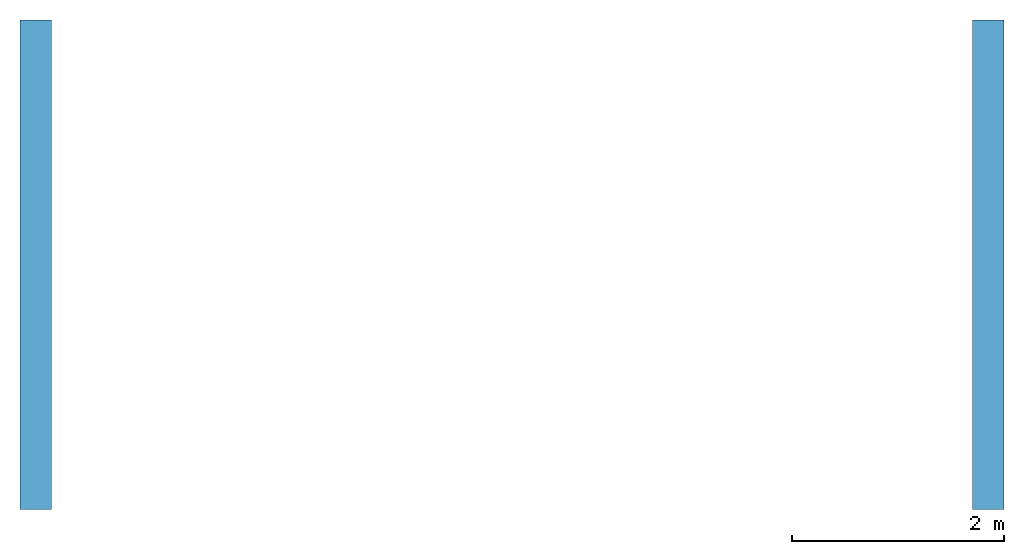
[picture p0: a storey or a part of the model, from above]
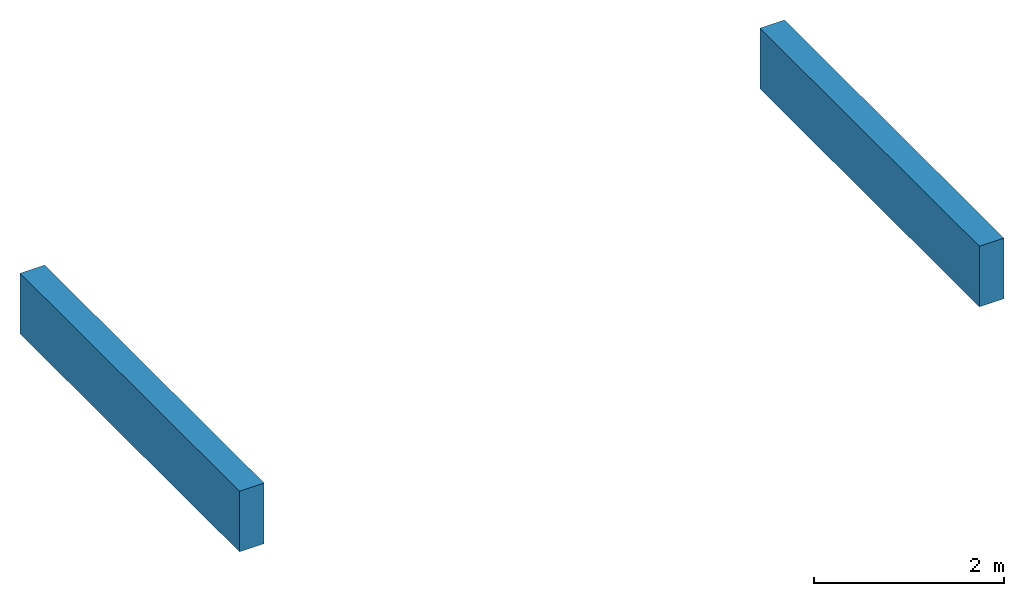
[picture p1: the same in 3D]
Properties of the parts of a building model (IFC2X3)

# File
Description: ViewDefinition [CoordinationView]
File name: GM.TO-350-101.1 (EDITED).ifc (Edited by Naviate Simple BIM 2022 version 6)
Time: 2026-03-17T17:04:53+01:00
Written by: ODA SDAI 24.12
Made in: Autodesk Revit 25.4.20.11 (ENU) - IFC 25.4.0.27

# IfcProject, A181143
LongName: T2; Phase: Detaljprosjekt

# IfcSite (9)
Name | RefLatitude | RefLongitude | RefElevation (mm) | Reference latitude | Reference elevation | Reference longitude
ENGM | 33, 12, 51, 119999 | -97, -7, -51, -239999 | -4.85124e-10
 | 33, 12, 51, 119999 | -97, -7, -51, -239999 | 0
 | 33, 12, 51, 119999 | -97, -7, -51, -239999 | 0 | 33, 12, 51, 119999 | 0 | -97, -7, -51, -239999
4 x ENGM | 59, 54, 49, 759826 | 10, 44, 19, 467315 | 0 | 59, 54, 49, 759826 | 0 | 10, 44, 19, 467315 | MagiCAD Pset_Site - Name: ENGM
Gardermoen
Default | 59, 54, 49, 759826 | 10, 44, 19, 467315 | 0

# IfcBuilding (9)
Name
TS | LongName: TS; Pset_BuildingCommon - NumberOfStoreys: 16
2 x mc-building
4 x TS | MagiCAD Pset_Building - Building name: TS
TS
 | Pset_BuildingCommon - NumberOfStoreys: 13

# IfcBuildingStorey (13)
Name | In | Elevation (mm) | Name
Nivå E | mc-building | 207370
Nivå D | mc-building | 204000
Nivå E | mc-building | 207370 | Nivå E
Nivå C | mc-building | 200300 | Nivå C
Nivå D | mc-building | 204000 | Nivå D
Nivå D + 1,2 m | mc-building | 205200 | Nivå D + 1,2 m
3 x Nivå D | TS | 204000 | Nivå D
D | TS | 0
B | TS | 0
2 x Nivå C | TS | 200300 | Nivå C

# IfcBuildingStorey: Level:8mm Head (2)
Pset_AirSideSystemInformation - sets with these values: 2
Name | LongName = Name | Elevation (mm)
Nivå C | Nivå C | 200300
Nivå D | Nivå D | 204000

# IfcBuildingStorey: Level:T2 - Kote (4)
In: TS
Name | LongName | Elevation (mm) | Pset_AirSideSystemInformation, Name | Pset_AirSideSystemInformation, sets with these values
Nivå C + 2,03 m | Nivå C + 2,03 m | 202330 | Nivå C + 2,03 m | 2
Nivå D | Nivå D | 204000 | Nivå D | 2
Nivå D + 1,2 m | Nivå D + 1,2 m | 205200 | Nivå D + 1,2 m | 2
Nivå E | Nivå E | 207370 | Pset_ProductRequirements - Name: Nivå E; sets with these values: 2

# IfcBeam: B223 - Bjelke - HUP:B223 - HUP 80x80x4 (5)
Type - Pset_BeamCommon - LoadBearing: yes
Material: _NSW Stål
Pset_BeamCommon - IsExternal: no; Slope: 0 deg; Reference: B223 - HUP 80x80x4; Span: 5920 mm
ePset_SimplebimBasicQuantities - Volume, net (Simplebim): 0.00719872 m3; Height (Simplebim): 80 mm; Width (Simplebim): 80 mm; Area, sides, net (Simplebim): 3.60179 m2; Length (Simplebim): 5920 mm; Weight, as steel (Simplebim): 56.51 kg
ePset_LocationTool - Splitting: ORIGINAL
Pset_QuantityTakeOff - Reference: B223 - HUP 80x80x4; sets with these values: 2
ePset_Simplebim - Assembly Level: Leaf
AVINOR - 07_Fase: F90; 08_Status: S1; 03_Ansvar: FDV; 06_Omrade: TS; 01_Lufthavnkode: ENGM
Name (B223 - Bjelke - HUP:B223 - HUP 80x80x4:...) | In
24003916 | Nivå E
24003994 | Nivå D
24003995 | Nivå E
24004007 | Nivå D
24004008 | Nivå E

# IfcBeam: RHS160*80*5 (4)
In: D
Description: RHS160*80*5; Material: STEEL/S355
ePset_LocationTool - Splitting: ORIGINAL
ePset_SimplebimBasicQuantities - Width (Simplebim): 80 mm; Height (Simplebim): 160 mm
Tekla Quantity - Width: 80 mm; Heigth: 160 mm
AVINOR - 07_Fase: F90; 02_Prosjekt: T1; 04_Kontrakt: FDV; 03_Ansvar: FDV; 08_Status: S2; 06_Omrade: TS; 01_Lufthavnkode: ENGM
ePset_Simplebim - Assembly Level: Leaf
Tekla Common - Grade: S355; Name: STÅLBJELKE; Bottom elevation: +207.090; Top elevation: +207.250; Profile: RHS160*80*5; Class: 330
Pset_BeamCommon - LoadBearing: no
Name | Area, sides, net (Simplebim) (m2) | Length (Simplebim) (mm) = Length (mm) | Weight, as steel (Simplebim) (kg) = WEIGTH_NET (kg) | Volume, net (Simplebim) (m3) | VOLUME_NET (m3) | WEIGTH_GROSS (kg) | VOLUME_GROSS (m3) | AREA_NET (m2) | AREA_GROSS (m2) | Assembly mark | Part mark = Reference
2 x STÅLBJELKE | 6.90371 | 7499.03 | 135.395 | 0.0172478 | 0.01724 | 134.806 | 0.01716 | 3.5632 | 3.51705 | SB-3277(?) | DSB-7490(?)
2 x STÅLBJELKE | 6.76568 | 7349 | 132.686 | 0.0169027 | 0.01689 | 132.109 | 0.01683 | 3.49196 | 3.44668 | SB-3275(?) | DSB-7488(?)

# IfcBeam: RHS80*5 (22)
In: D
Description: RHS80*5
Pset_BeamCommon - LoadBearing: no
AVINOR - 07_Fase: F90; 02_Prosjekt: T1; 04_Kontrakt: FDV; 03_Ansvar: FDV; 08_Status: S2; 06_Omrade: TS; 01_Lufthavnkode: ENGM
Tekla Common - Grade: S355; Profile: RHS80*5; Name: STÅLBJELKE; Class: 330
ePset_Simplebim - Assembly Level: Leaf
ePset_SimplebimBasicQuantities - Width (Simplebim): 80 mm
Name | Material | WEIGTH_NET (kg) | AREA_NET (m2) | Length (mm) | VOLUME_GROSS (m3) | AREA_GROSS (m2) | Heigth (mm) = Width (mm) | WEIGTH_GROSS (kg) | VOLUME_NET (m3) | Reference = Part mark | Splitting | Assembly mark | Top elevation | Bottom elevation | Volume, net (Simplebim) (m3) | Height (Simplebim) (mm) | Weight, as steel (Simplebim) (kg) | Length (Simplebim) (mm) | Area, sides, net (Simplebim) (m2)
15 x STÅLBJELKE | STEEL/S355 | 6.94726 | 0.1904 | 590.001 | 0.00087 | 0.18231 | 80 | 6.90094 | 0.00089 | DSB-15340(?) | ORIGINAL | SB-3284(?) | +207.170 | +206.580 | 0.000885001 | 590.001 | 6.94726 | 80 | 0.357
STÅLBJELKE | STEEL/S355 | 16.7088 | 0.45568 | 1419.01 | 0.00211 | 0.43847 | 80 | 16.5974 | 0.00214 | DSB-7509(?) | ORIGINAL | SB-3289(?) | +206.210 | +206.130 | 0.00212851 | 80 | 16.7088 | 1419.01 | 0.854403
STÅLBJELKE | STEEL/S355 | 4.79243 | 0.13184 | 407 | 0.00062 | 0.12576 | 80 | 4.76048 | 0.00062 | DSB-7506(?) | ORIGINAL | SB-3286(?) | +206.580 | +206.500 | 0.0006105 | 80 | 4.79242 | 407 | 0.2472
STÅLBJELKE | STEEL/S355 | 63.9737 | 1.74016 | 5433.01 | 0.0081 | 1.6788 | 80 | 63.5472 | 0.00815 | DSB-7507(?) | ORIGINAL | SB-3287(?) | +206.580 | +206.500 | 0.00814951 | 80 | 63.9737 | 5433.01 | 3.26281
STÅLBJELKE | STEEL/S355 | 69.708 | 1.896 | 5920 | 0.00882 | 1.82928 | 80 | 69.2433 | 0.00887 | DSB-7508(?) | ORIGINAL | SB-3288(?) | +206.580 | +206.500 | 0.00888 | 80 | 69.708 | 5920 | 3.555
STÅLBJELKE | STEEL/S355 | 63.9736 | 1.74016 | 5433 | 0.0081 | 1.6788 | 80 | 63.5471 | 0.00815 | DSB-7507(?) | ORIGINAL | SB-3287(?) | +206.580 | +206.500 | 0.00814951 | 80 | 63.9737 | 5433.01 | 3.26281
STÅLBJELKE | STEEL/S355 | 4.79233 | 0.13184 | 406.992 | 0.00062 | 0.12576 | 80 | 4.76038 | 0.00062 | DSB-7506(?) | ORIGINAL | SB-3286(?) | +206.580 | +206.500 | 0.0006105 | 80 | 4.79242 | 407 | 0.2472
STÅLBJELKE |  |  |  |  |  |  |  |  |  | DSB-7504(?) | RESULT | SB-3284(?) | +207.250 | +207.170 | 0.0260302 | 80 | 204.337 | 17353 | 10.4151

# IfcBuildingElementProxy, KRO Damphette 1350x1400x500_tilkobling i front
In: Nivå D
ePset_LocationTool - Splitting: ORIGINAL
ePset_Simplebim - Assembly Level: Leaf
ePset_SimplebimBasicQuantities - Area, largest surface, net (Simplebim): 1.89 m2; Length (Simplebim): 1420 mm; Volume, net (Simplebim): 0.9466 m3; Height (Simplebim): 500 mm; Thickness (Simplebim): 1350 mm
Group: +TS=360.034 A (1)

# IfcBuildingElementProxy: A234 - Gitter:A241 - Gitter 200 x 200_UK_2600, A234 - Gitter:A241 - Gitter 200 x 200_UK_2600:30921747
In: Nivå D
Type - Material: <Unnamed>
Pset_BuildingElementProxyCommon - Reference: A241 - Gitter 200 x 200_UK_2600; sets with these values: 2
AVINOR - 07_Fase: F90; 08_Status: S1; 03_Ansvar: FDV; 06_Omrade: TS; 01_Lufthavnkode: ENGM
ePset_Simplebim - Assembly Level: Leaf
ePset_SimplebimBasicQuantities - Volume, net (Simplebim): 0.90288 m3; Area, largest surface, net (Simplebim): 4.104 m2; Length (Simplebim): 17100 mm; Thickness (Simplebim): 240 mm; Height (Simplebim): 220 mm
ePset_LocationTool - Splitting: ORIGINAL

# IfcColumn: PL15*260 (12)
In: D
Description: PL15*260; Material: STEEL/S355
Pset_ColumnCommon - LoadBearing: no; Reference: DSS-5570(?)
Tekla Quantity - VOLUME_NET: 0.00047 m3; VOLUME_GROSS: 0.00047 m3; AREA_NET: 0.0738 m2; AREA_GROSS: 0.0738 m2; WEIGTH_GROSS: 3.6738 kg; WEIGTH_NET: 3.6738 kg; Width: 15 mm; Length: 120 mm; Heigth: 260 mm
ePset_SimplebimBasicQuantities - Volume, net (Simplebim): 0.000468 m3; Weight, as steel (Simplebim): 3.6738 kg; Area, sides, net (Simplebim): 0.0114 m2; Width (Simplebim): 15 mm; Depth (Simplebim): 120 mm; Height (Simplebim): 260 mm
AVINOR - 07_Fase: F90; 02_Prosjekt: T1; 03_Ansvar: FDV; 04_Kontrakt: FDV; 08_Status: S2; 06_Omrade: TS; 01_Lufthavnkode: ENGM
ePset_LocationTool - Splitting: ORIGINAL
Tekla Common - Grade: S355; Class: 320; Profile: PL15*260; Name: STÅLSØYLE; Part mark: DSS-5570(?)
ePset_Simplebim - Assembly Level: Leaf
Name | Assembly mark | Bottom elevation | Top elevation
6 x STÅLSØYLE | SS-2790(?) | +203.930 | +203.945
STÅLSØYLE | SS-8193(?) | +203.935 | +203.950
4 x STÅLSØYLE | SS-2789(?) | +203.930 | +203.945
STÅLSØYLE | SS-1401(?) | +203.930 | +203.945

# IfcColumn: RHS80*5 (12)
In: D
Description: RHS80*5; Material: STEEL/S355
ePset_LocationTool - Splitting: ORIGINAL
Tekla Common - Grade: S355; Profile: RHS80*5; Class: 320; Name: STÅLSØYLE
ePset_SimplebimBasicQuantities - Width (Simplebim): 80 mm; Depth (Simplebim): 80 mm
AVINOR - 07_Fase: F90; 02_Prosjekt: T1; 03_Ansvar: FDV; 04_Kontrakt: FDV; 08_Status: S2; 06_Omrade: TS; 01_Lufthavnkode: ENGM
Pset_ColumnCommon - LoadBearing: no
ePset_Simplebim - Assembly Level: Leaf
Tekla Quantity - Width: 80 mm; Heigth: 80 mm
Name | Assembly mark | Part mark = Reference | Top elevation | Bottom elevation | Volume, net (Simplebim) (m3) | Height (Simplebim) (mm) = Length (mm) | Area, sides, net (Simplebim) (m2) | Weight, as steel (Simplebim) (kg) = WEIGTH_NET (kg) | AREA_NET (m2) | VOLUME_NET (m3) | WEIGTH_GROSS (kg) | AREA_GROSS (m2) | VOLUME_GROSS (m3)
6 x STÅLSØYLE | SS-2790(?) | DSS-1715(?) | +207.090 | +203.945 | 0.0047175 | 3145 | 1.887 | 37.0324 | 1.008 | 0.00471 | 36.7855 | 0.9718 | 0.00469
STÅLSØYLE | SS-8193(?) | DSS-3492(?) | +207.170 | +203.950 | 0.00483 | 3220 | 1.932 | 37.9155 | 1.032 | 0.00483 | 37.6627 | 0.99498 | 0.0048
4 x STÅLSØYLE | SS-2789(?) | DSS-1716(?) | +207.170 | +203.945 | 0.0048375 | 3225 | 1.935 | 37.9744 | 1.0336 | 0.00484 | 37.7212 | 0.99652 | 0.0048
STÅLSØYLE | SS-1401(?) | DSS-1716(?) | +207.170 | +203.945 | 0.0048375 | 3225 | 1.935 | 37.9744 | 1.0336 | 0.00484 | 37.7212 | 0.99652 | 0.0048

# IfcCovering (33)
PredefinedType: INSULATION
ePset_LocationTool - Splitting: ORIGINAL
ePset_Simplebim - Assembly Level: Leaf
Name | In | Description | Volume, net (Simplebim) (m3) | Length (Simplebim) (mm) | Height (Simplebim) (mm) | Width (Simplebim) (mm) | Area, largest surface, net (Simplebim) (m2)
EI30-30 | Nivå E | EI30 Brannisolasjon 30 mm | 0.102218 | 3159.7 | 375 | 375 | 3.71771
EI30-30 | Nivå E | EI30 Brannisolasjon 30 mm | 0.0403898 | 1248.5 | 375 | 375 | 1.46899
EI30-30 | Nivå E | EI30 Brannisolasjon 30 mm | 0.0269438 | 412.344 | 375 | 355.321 | 0.289607
EI30-30 | Nivå E | EI30 Brannisolasjon 30 mm | 0.0322994 | 376.5 | 376.5 | 375 | 0.346444
T=25mm | Nivå E | 25mm lamellmatte | 0.000823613 | 365 | 31 | 365 | 0.035502
EI30-30 | Nivå E | EI30 Brannisolasjon 30 mm | 0.00602371 | 55 | 375 | 375 | 0.109522
EI30-30 | Nivå E | EI30 Brannisolasjon 30 mm | 0.0811775 | 2509.3 | 375 | 375 | 2.95245
EI30-30 | Nivå E | EI30 Brannisolasjon 30 mm | 0.0537249 | 502.5 | 375 | 502.5 | 0.57858
EI30-30 | Nivå D | EI30 Brannisolasjon 30 mm | 0.0242953 | 751 | 375 | 375 | 0.883628
T=25mm | Nivå D | 25mm lamellmatte | 0.0619889 | 2333.2 | 365 | 365 | 2.67204
EI30-50 | Nivå D | EI30 Brannisolasjon 50 mm | 0.0110508 | 350 | 235.7 | 350 | 0.258837
T=25mm | Nivå D | 25mm lamellmatte | 0.00566433 | 213.2 | 365 | 365 | 0.244162
T=25mm | Nivå D | 25mm lamellmatte | 0.00458301 | 365 | 172.5 | 365 | 0.197552
T=25mm | Nivå D | 25mm lamellmatte | 0.030022 | 1130 | 365 | 365 | 1.29411
T=25mm | Nivå D | 25mm lamellmatte | 0.0305888 | 365 | 371.5 | 371.5 | 0.338062
T=25mm | Nivå D | 25mm lamellmatte | 0.0225404 | 848.4 | 365 | 365 | 0.97161
T=25mm | Nivå D | 25mm lamellmatte | 0.0182478 | 365 | 176.404 | 365 | 0.201702
2 x EI30-50 | Nivå D | EI30 Brannisolasjon 50 mm | 0.0188986 | 483.7 | 300 | 300 | 0.455298
EI30-50 | Nivå D | EI30 Brannisolasjon 50 mm | 0.0444048 | 947.1 | 350 | 350 | 1.04007
EI30-50 | Nivå D | EI30 Brannisolasjon 50 mm | 0.00615391 | 88.0625 | 300 | 300 | 0.0827602
EI30-50 | Nivå D | EI30 Brannisolasjon 50 mm | 0.0061529 | 88.048 | 300 | 300 | 0.0827465
EI30-50 | Nivå D | EI30 Brannisolasjon 50 mm | 0.00570696 | 60 | 350 | 350 | 0.095116
EI30-30 | Nivå D | EI30 Brannisolasjon 30 mm | 0.00276153 | 58.9 | 350 | 350 | 0.0646818
EI30-30 | Nivå D | EI30 Brannisolasjon 30 mm | 0.0247587 | 387.5 | 368.061 | 350 | 0.285647
EI30-30 | Nivå D | EI30 Brannisolasjon 30 mm | 0.0123856 | 360.048 | 350 | 212.5 | 0.142824
T=25mm | Nivå D | 25mm lamellmatte | 0.00674832 | 365 | 365 | 254 | 0.290888
2 x T=25mm | Nivå D | 25mm lamellmatte | 0.0254885 | 403.808 | 365 | 351.786 | 0.28172
T=25mm | Nivå D | 25mm lamellmatte | 0.00553681 | 208.4 | 365 | 365 | 0.238665
2 x T=25mm | Nivå D | 25mm lamellmatte | 0.0169708 | 382.752 | 365 | 248.75 | 0.187679
EI30-30 | Nivå D | EI30 Brannisolasjon 30 mm | 0.0592599 | 1831.8 | 375 | 375 | 2.1553

# IfcDistributionControlElement: Brann Spjeld (2)
In: Nivå D
Type - Description: Brann Spjeld
ePset_LocationTool - Splitting: ORIGINAL
MagiCAD Pset_Device - System code: 542; Length [mm]: 0 mm; Width [mm]: 0 mm; Height [mm]: 0 mm; O1: 1; Manufacturer: General
ePset_Simplebim - Assembly Level: Leaf
Group: -

# IfcDistributionControlElement: Brannalarm Multikriteriedetektor OT Blue
In: Nivå D
Type - Description: Brannalarm Multikriteriedetektor OT Blue
MagiCAD Pset_Device - System code: 542; User code: -TY; Length [mm]: 0 mm; Width [mm]: 0 mm; Height [mm]: 0 mm; Installation Code: 2
ePset_LocationTool - Splitting: ORIGINAL
ePset_Simplebim - Assembly Level: Leaf
Group: Brannalarm

# IfcDistributionControlElement: Nødåpner
In: Nivå D
Type - Description: Nødåpner KAC
AVINOR - 08_Status: S4; 07_Fase: F90; 05_ID-nummer: +TS=277.007-IK0001; 02_Prosjekt: 10003733; 03_Ansvar: 187259; 04_Kontrakt: 188773; 01_Lufthavnkode: ENGM
Pset_ElectricalDeviceCommon - IP_Code: IP20
ePset_LocationTool - Splitting: ORIGINAL
ePset_Simplebim - Assembly Level: Leaf
MagiCAD Pset_Device - System code: 543; User code: -IK; IP_Code: IP20; P1: -XS; Length [mm]: 0 mm; Width [mm]: 0 mm; Height [mm]: 0 mm; Manufacturer: General
Group: Adgangskontroll, Innbruddsalarm

# IfcDistributionControlElement: Standard (10)
Type - Description: Brannalarm Røykdetektor
ePset_LocationTool - Splitting: ORIGINAL
MagiCAD Pset_Device - Length [mm]: 0 mm; Width [mm]: 0 mm; Height [mm]: 0 mm
ePset_Simplebim - Assembly Level: Leaf
Name | In | Description | Classification | User code | P1 | National code | System code | Installation Code | Manufacturer | Group
2 x Standard | Nivå D | Brannalarm Multikriteriedetektor over himling | XJ1.1115 Not defined (NS3420) | -TY | -TY | XJ1.1115
Standard | Nivå D | Brannalarm Multikriteriedetektor | XJ1.1115 Not defined (NS3420) | -TY | -TY | XJ1.1115 | 542 | 2 | General | Brannalarm
Standard | Nivå D | Brannalarm Røykdetektor over himling |  | -TY |  |  | 542 | 3 |  | Brannalarm
Standard | Nivå D | Brannalarm Parallell lampe |  |  | -OS |  | 542 | 2 |  | Brannalarm
Standard | Nivå D | Brannalarm Dørholdemagnet | XJ4.1 Not defined (NS3420) |  | -QZ | XJ4.1 |  |  | General | Pset_ElectricalDeviceCommon - IP_Code: IP54; MagiCAD Pset_Device - Host: +TS=542.004; Circuit order no: 45; IP_Code: IP54
4 x Standard | Nivå C |  | XJ1.1115 Not defined (NS3420) | -TY | -RY | XJ1.1115 | 542 | 2 | General | Brannalarm | Pset_ElectricalDeviceCommon - IP_Code: IP20; MagiCAD Pset_Device - Circuit order no: <unnamed>; IP_Code: IP20

# IfcDistributionControlElement: Switch with one push button
In: Nivå D
Type - Description: Åpneknapp
MagiCAD Pset_Device - Product code: Switch with one push button; System code: 543; P1: -QG; Length [mm]: 0 mm; Manufacturer: General; Width [mm]: 10 mm; Height [mm]: 60 mm; IP_Code: IP21
ePset_LocationTool - Splitting: ORIGINAL
AVINOR - 03_Ansvar: 187981; 08_Status: S2; 02_Prosjekt: A10001716; 07_Fase: F30; 01_Lufthavnkode: ENGM
ePset_Simplebim - Assembly Level: Leaf
Pset_ElectricalDeviceCommon - IP_Code: IP21
Group: Adgangskontroll, Innbruddsalarm

# IfcDistributionPort (12)
Description: Flow; FlowDirection: SOURCEANDSINK
ePset_Simplebim - Assembly Level: Leaf
Name
Port_18524484_1
Port_18524501_1
Port_18528150_1
2 x Port_18528168_1
2 x Port_24788155_1
Port_19542616_1
2 x Port_19542617_1
Port_24787859_1
Port_24788283_1

# IfcDoor: A20 - Slagdør - Enkel:A243 - DI_LTO - 0990 x 2090 mm, A20 - Slagdør - Enkel:A243 - DI_LTO - 0990 x 2090 mm:30610669
In: Nivå D
Type - OperationType: SINGLE_SWING_RIGHT; ParameterTakesPrecedence: no; Sizeable: no; Material: N_Door - Handle, _NSW Stål - rustfritt, _NSW Dør - karm, hvit, N_Door - Threshold, N_Door - Panel
Type - IfcDoorPanelProperties - PanelOperation: SWINGING
OverallHeight: 2110 mm; OverallWidth: 1010 mm
Pset_DoorCommon - Reference: A243 - DI_LTO - 0990 x 2090 mm; IsExternal: no
ePset_SimplebimBasicQuantities - Height, opening (Simplebim): 2110 mm; Area (Simplebim): 2.0691 m2; Width (Simplebim): 990 mm; Width, opening (Simplebim): 1010 mm; Height (Simplebim): 2090 mm; Length, frame (Simplebim): 5170 mm; Area, opening (Simplebim): 2.1311 m2
ePset_LocationTool - Splitting: ORIGINAL
Pset_QuantityTakeOff - Reference: A243 - DI_LTO - 0990 x 2090 mm
ePset_Simplebim - Assembly Level: Leaf
AVINOR - 07_Fase: F90; 03_Ansvar: FDV; 08_Status: S2; 06_Omrade: TS; 01_Lufthavnkode: ENGM

# IfcDoor: A20 - Slagdør - Enkel:A243 - DI_LTO - 890 x 2090 mm, A20 - Slagdør - Enkel:A243 - DI_LTO - 890 x 2090 mm:32536192
In: Nivå D
Type - OperationType: SINGLE_SWING_RIGHT; ParameterTakesPrecedence: no; Sizeable: no; Material: N_Door - Handle, _NSW Stål - rustfritt, _NSW Dør - karm, hvit, N_Door - Threshold, N_Door - Panel
Type - IfcDoorPanelProperties - PanelOperation: SWINGING
OverallHeight: 2110 mm; OverallWidth: 910 mm
ePset_LocationTool - Splitting: ORIGINAL
Pset_DoorCommon - IsExternal: no; Reference: A243 - DI_LTO - 890 x 2090 mm
ePset_SimplebimBasicQuantities - Height, opening (Simplebim): 2110 mm; Area, opening (Simplebim): 1.9201 m2; Area (Simplebim): 1.8601 m2; Width, opening (Simplebim): 910 mm; Width (Simplebim): 890 mm; Height (Simplebim): 2090 mm; Length, frame (Simplebim): 5070 mm
Pset_QuantityTakeOff - Reference: A243 - DI_LTO - 890 x 2090 mm
ePset_Simplebim - Assembly Level: Leaf
AVINOR - 07_Fase: F90; 03_Ansvar: FDV; 08_Status: S2; 06_Omrade: TS; 01_Lufthavnkode: ENGM

# IfcFlowController: IGNIS-C-EI30-250
In: Nivå D
Type - Description: CIRCULAR FIRE DAMPER CLASS EI30; PredefinedType: FIREDAMPER
ePset_LocationTool - Splitting: ORIGINAL
ePset_Simplebim - Assembly Level: Leaf
Group: +TS=360.034 A (1)

# IfcFlowController: IGNIS-C-EI30-315
In: Nivå D
Type - Description: CIRCULAR FIRE DAMPER CLASS EI30; PredefinedType: FIREDAMPER
ePset_LocationTool - Splitting: ORIGINAL
ePset_Simplebim - Assembly Level: Leaf
Group: +TS=360.034 T (1)

# IfcFlowController: IRIS-315
In: Nivå E
Type - PredefinedType: BALANCINGDAMPER
ePset_Simplebim - Assembly Level: Leaf
ePset_LocationTool - Splitting: ORIGINAL
Group: +TS=360.050 A

# IfcFlowFitting: 10mm Radius (3)
In: Nivå C
Type - PredefinedType: TEE
ePset_LocationTool - Splitting: ORIGINAL
MagiCAD Pset_Cabletray - System code: 4111; Width [mm]: 0 mm; Height [mm]: 0 mm; Length [mm]: 0 mm
ePset_Simplebim - Assembly Level: Leaf
Group: Bæresystem for elkraft

# IfcFlowFitting: Grensesnittboks (2)
In: Nivå D
Type - Description: Grensesnitt kabling
AVINOR - 08_Status: S4; 04_Kontrakt: 184332; 02_Prosjekt: A181143; 09_Arbeidspakke: K0D; 03_Ansvar: 187259; 07_Fase: F50; 01_Lufthavnkode: ENGM
MagiCAD Pset_Device - System code: 543; Product code: -QM_Koblingsboks; User code: -QM; P1: -WD; Length [mm]: 0 mm; Width [mm]: 0 mm; Height [mm]: 0 mm; O2: 543.007; Manufacturer: General
ePset_LocationTool - Splitting: ORIGINAL
ePset_Simplebim - Assembly Level: Leaf
Group: Adgangskontroll, Innbruddsalarm
Name | 05_ID-nummer
Grensesnittboks | +TS=543.007-QM0004
Grensesnittboks | +TS=543.007-QM0101

# IfcFlowFitting: Standard 10mm
In: Nivå C
Type - PredefinedType: BEND
MagiCAD Pset_Cabletray - System code: 4111; Width [mm]: 0 mm; Height [mm]: 0 mm; Length [mm]: 0 mm
ePset_LocationTool - Splitting: ORIGINAL
ePset_Simplebim - Assembly Level: Leaf
Group: Bæresystem for elkraft

# IfcFlowFitting: magi_pipe_fe_cross_centric_90_001 (4)
In: Nivå C
Type - PredefinedType: JUNCTION
MagiCAD Pset_XBranch - Insulation_thickness_mm: 0 mm; qv_SizingFlow_ls: 0 m3/s; pTot_SizingFlow_Pa: 0 kPa; dpTot_SizingFlow_Pa: 0 kPa; v_SizingFlow_ms: 0 m/s; ConnectionSize_mm: 0 mm
ePset_LocationTool - Splitting: ORIGINAL
ePset_Simplebim - Assembly Level: Leaf
Group: +TS=332.002

# IfcFlowFitting: magi_pipe_fe_elbow_short_001 (33)
Type - PredefinedType: BEND
MagiCAD Pset_Elbow - Insulation_thickness_mm: 0 mm; qv_SizingFlow_ls: 0 m3/s; pTot_SizingFlow_Pa: 0 kPa; dpTot_SizingFlow_Pa: 0 kPa; v_SizingFlow_ms: 0 m/s; ConnectionSize_mm: 0 mm
ePset_LocationTool - Splitting: ORIGINAL
ePset_Simplebim - Assembly Level: Leaf
Name | In | Group
12 x magi_pipe_fe_elbow_short_001 | Nivå C | +TS=332.002
2 x magi_pipe_fe_elbow_short_001 | Nivå D | 33= Våt Kopi 1
19 x magi_pipe_fe_elbow_short_001 | Nivå D | +TS=332.008

# IfcFlowFitting: magi_pipe_fe_reducer_centric_short_NOR (29)
Type - PredefinedType: TRANSITION
MagiCAD Pset_Reduction - Insulation_thickness_mm: 0 mm; qv_SizingFlow_ls: 0 m3/s; pTot_SizingFlow_Pa: 0 kPa; dpTot_SizingFlow_Pa: 0 kPa; v_SizingFlow_ms: 0 m/s; ConnectionSize_mm: 0 mm
ePset_LocationTool - Splitting: ORIGINAL
ePset_Simplebim - Assembly Level: Leaf
Name | In | Group
magi_pipe_fe_reducer_centric_short_NOR | Nivå E | +TS=332.008
14 x magi_pipe_fe_reducer_centric_short_NOR | Nivå C | +TS=332.002
3 x magi_pipe_fe_reducer_centric_short_NOR | Nivå D | 33= Våt Kopi 1
5 x magi_pipe_fe_reducer_centric_short_NOR | Nivå D | +TS=332.008
magi_pipe_fe_reducer_centric_short_NOR | Nivå D | 33= Våt Kopi 27
magi_pipe_fe_reducer_centric_short_NOR | Nivå D + 1,2 m | 33= Våt Kopi 29
magi_pipe_fe_reducer_centric_short_NOR | Nivå D + 1,2 m | 33= Våt Kopi 40
magi_pipe_fe_reducer_centric_short_NOR | Nivå D + 1,2 m | 33= Våt Kopi 43
magi_pipe_fe_reducer_centric_short_NOR | Nivå D + 1,2 m | 33= Våt Kopi 48
magi_pipe_fe_reducer_centric_short_NOR | Nivå D + 1,2 m | 33= Våt Kopi 47

# IfcFlowFitting: magi_pipe_fe_tee_centric_90_NOR (17)
Type - PredefinedType: JUNCTION
MagiCAD Pset_TBranch - Insulation_thickness_mm: 0 mm; qv_SizingFlow_ls: 0 m3/s; pTot_SizingFlow_Pa: 0 kPa; dpTot_SizingFlow_Pa: 0 kPa; v_SizingFlow_ms: 0 m/s; ConnectionSize_mm: 0 mm
ePset_LocationTool - Splitting: ORIGINAL
ePset_Simplebim - Assembly Level: Leaf
Name | In | Group
magi_pipe_fe_tee_centric_90_NOR | Nivå E | +TS=332.008
6 x magi_pipe_fe_tee_centric_90_NOR | Nivå C | +TS=332.002
5 x magi_pipe_fe_tee_centric_90_NOR | Nivå D | +TS=332.008
5 x magi_pipe_fe_tee_centric_90_NOR | Nivå D + 1,2 m | +TS=332.008

# IfcFlowFitting: magicirc_elbow_full_radius_001 (9)
Type - Description: Circular, smooth,R=D; PredefinedType: BEND
ePset_LocationTool - Splitting: ORIGINAL
ePset_Simplebim - Assembly Level: Leaf
Name | In | Group
2 x magicirc_elbow_full_radius_001 | Nivå E | +TS=360.050 A
2 x magicirc_elbow_full_radius_001 | Nivå D | +TS=360.034 A (1)
4 x magicirc_elbow_full_radius_001 | Nivå D | +TS=360.034 T (1)
magicirc_elbow_full_radius_001 | Nivå D | +TS=360.050 A | Description: Bend, Sirkulært

# IfcFlowFitting: magicirc_elbow_short_001 (2)
Type - PredefinedType: BEND
ePset_LocationTool - Splitting: ORIGINAL
ePset_Simplebim - Assembly Level: Leaf
Name | In | Group
magicirc_elbow_short_001 | Nivå E | +TS=360.050 A
magicirc_elbow_short_001 | Nivå D | +TS=360.034 T (1)

# IfcFlowFitting: magicirc_plug_001
In: Nivå D
Type - Description: Circular; PredefinedType: OBSTRUCTION
ePset_LocationTool - Splitting: ORIGINAL
ePset_Simplebim - Assembly Level: Leaf
Group: +TS=360.034 A (1)

# IfcFlowFitting: magicirc_tapoutlet_001 (3)
In: Nivå D
Type - Description: Rectangular/circular; PredefinedType: CONNECTOR
ePset_LocationTool - Splitting: ORIGINAL
ePset_Simplebim - Assembly Level: Leaf
Name | Group
magicirc_tapoutlet_001 | +TS=360.034 T (1) | Description: Påstikk
2 x magicirc_tapoutlet_001 | +TS=360.034 A (1)

# IfcFlowSegment: KK001T - Spiro kanaler, Forsinket stål (13)
Type - Description: Spiro kanaler, Forsinket stål; PredefinedType: RIGIDSEGMENT
Classification: VB2.121212 Not defined (NS3420)
ePset_LocationTool - Splitting: ORIGINAL
ePset_Simplebim - Assembly Level: Leaf
Name | In | Length (Simplebim) (mm) | Height (Simplebim) (mm) | Width (Simplebim) (mm) | Group
KK001T - Spiro kanaler, Forsinket stål | Nivå E | 3159.7 | 315 | 315 | +TS=360.050 A
KK001T - Spiro kanaler, Forsinket stål | Nivå E | 1248.5 | 315 | 315 | +TS=360.050 A
KK001T - Spiro kanaler, Forsinket stål | Nivå E | 2509.3 | 315 | 315 | +TS=360.050 A
KK001T - Spiro kanaler, Forsinket stål | Nivå D | 751 | 315 | 315 | +TS=360.050 A
KK001T - Spiro kanaler, Forsinket stål | Nivå D | 250 | 236.1 | 250 | +TS=360.034 A (1)
KK001T - Spiro kanaler, Forsinket stål | Nivå D | 315 | 172.5 | 315 | +TS=360.034 T (1)
KK001T - Spiro kanaler, Forsinket stål | Nivå D | 1130 | 315 | 315 | +TS=360.034 T (1)
KK001T - Spiro kanaler, Forsinket stål | Nivå D | 848.4 | 315 | 315 | +TS=360.034 T (1)
KK001T - Spiro kanaler, Forsinket stål | Nivå D | 946.7 | 250 | 250 | +TS=360.034 A (1)
KK001T - Spiro kanaler, Forsinket stål | Nivå D | 58.9 | 250 | 250 | +TS=360.034 A (1)
KK001T - Spiro kanaler, Forsinket stål | Nivå D | 315 | 315 | 254 | +TS=360.034 T (1)
KK001T - Spiro kanaler, Forsinket stål | Nivå D | 1832.3 | 315 | 315 | +TS=360.050 A
KK001T - Spiro kanaler, Forsinket stål | Nivå D | 1825 | 315 | 315 | +TS=360.050 A

# IfcFlowSegment: Kabelbro (9)
In: Nivå C
Type - PredefinedType: CABLELADDERSEGMENT
ePset_SimplebimBasicQuantities - Height (Simplebim): 60 mm
ePset_Simplebim - Assembly Level: Leaf
Name | Width (Simplebim) (mm) | Length (Simplebim) (mm) | Length [mm] (mm) = NominalLength (mm) | System code | Height [mm] (mm) = NominalHeight (mm) | Width [mm] (mm) = NominalWidth (mm) | Splitting | Group
Kabelbro | 600 | 2562.58 | 2562.58 | 4111 | 60 | 600 | ORIGINAL | Bæresystem for elkraft
Kabelbro | 600 | 3679 | 3679.49 | 4111 | 60 | 600 | ORIGINAL | Bæresystem for elkraft
Kabelbro | 600 | 1660.3 | 1660.31 | 4111 | 60 | 600 | ORIGINAL | Bæresystem for elkraft
Kabelbro | 37.5478 | 600 | 37.548 |  | 60 | 600 | ORIGINAL
Kabelbro | 171.009 | 600 | 170.851 | 4111 | 60 | 600 | ORIGINAL | Bæresystem for elkraft
Kabelbro | 600 | 900 | 900 | 4111 | 60 | 600 | ORIGINAL | Bæresystem for elkraft
Kabelbro | 600 | 1711.19 | 1711.19 | 4111 | 60 | 600 | ORIGINAL | Bæresystem for elkraft
Kabelbro | 600 | 2744.7 | 2744.7 | 4111 | 60 | 600 | ORIGINAL | Bæresystem for elkraft
Kabelbro | 600 | 717 |  | 4111 |  |  | RESULT | Bæresystem for elkraft

# IfcFlowSegment: Sirkulær kanal (6)
Type - Description: Sirkulær kanal, forsinket stål; PredefinedType: RIGIDSEGMENT
ePset_LocationTool - Splitting: ORIGINAL
ePset_Simplebim - Assembly Level: Leaf
Name | In | Height (Simplebim) (mm) | Length (Simplebim) (mm) | Width (Simplebim) (mm) | Group
Sirkulær kanal | Nivå E | 31 | 315 | 315 | +TS=360.034 T (1)
Sirkulær kanal | Nivå D | 315 | 2333.2 | 315 | +TS=360.034 T (1)
Sirkulær kanal | Nivå D | 315 | 213 | 315 | +TS=360.034 T (1)
2 x Sirkulær kanal | Nivå D | 200 | 483.7 | 200 | +TS=360.034 A (1)
Sirkulær kanal | Nivå D | 315 | 208.4 | 315 | +TS=360.034 T (1)

# IfcFlowSegment: Stålrør normaltykke (82)
Type - PredefinedType: RIGIDSEGMENT
Classification: UB3.144613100 Not defined (NS3420)
MagiCAD Pset_Pipe - SystemClass: Fire Protection Wet; NationalCode: UB3.144613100; Product variable 1: DN; User Code: DN; Material: Stålrør normaltykke
ePset_Simplebim - Assembly Level: Leaf
Name | In | Length_mm (mm) | SystemName = Group | SystemType | Insulation_thickness_mm (mm) = qv_SizingFlow_ls (m3/s) = MagiCAD Pset_Heating, v_SizingFlow_ms (m/s) = MagiCAD Pset_Heating, pTot_SizingFlow_kPa (kPa) = MagiCAD Pset_Heating, dpTot_SizingFlow_kPa (kPa) = MagiCAD Pset_Water, dpTot_SizingFlow_kPa (kPa) = MagiCAD Pset_Water, pTot_SizingFlow_kPa (kPa) = MagiCAD Pset_Water, v_SizingFlow_ms (m/s) | ConnectionSize_mm (mm) | Splitting | Width (Simplebim) (mm) | Height (Simplebim) (mm) | Length (Simplebim) (mm)
Stålrør normaltykke | Nivå E | 252.65 | +TS=332.008 | SPRINKEL | 0 | 40 | ORIGINAL | 48.2 | 48.2 | 252.7
Stålrør normaltykke | Nivå E | 63.15 | +TS=332.008 | SPRINKEL | 0 | 50 | ORIGINAL | 60.2 | 60.2 | 63.1
Stålrør normaltykke | Nivå E | 2554.9 | +TS=332.008 | SPRINKEL | 0 | 25 | ORIGINAL | 33.8 | 33.8 | 2555.3
5 x Stålrør normaltykke | Nivå C | 37.298 | +TS=332.002 | SPRINKEL | 0 | 25 | ORIGINAL | 33.8 | 33.8 | 37.3
5 x Stålrør normaltykke | Nivå C | 2937.4 | +TS=332.002 | SPRINKEL | 0 | 25 | ORIGINAL | 33.8 | 33.8 | 2937.4
9 x Stålrør normaltykke | Nivå C | 28.848 | +TS=332.002 | SPRINKEL | 0 | 25 | ORIGINAL | 33.8 | 28.8 | 33.8
4 x Stålrør normaltykke | Nivå C | 457.855 | +TS=332.002 | SPRINKEL | 0 | 25 | ORIGINAL | 33.8 | 33.8 | 458.3
Stålrør normaltykke | Nivå C | 2169.89 | +TS=332.002 | SPRINKEL | 0 | 40 | ORIGINAL | 48.2 | 48.2 | 2169.9
2 x Stålrør normaltykke | Nivå C | 136.2 | +TS=332.002 | SPRINKEL | 0 | 25 | ORIGINAL | 33.8 | 33.8 | 135.9
Stålrør normaltykke | Nivå C | 519.832 | +TS=332.002 | SPRINKEL | 0 | 25 | ORIGINAL | 33.8 | 33.8 | 519.8
Stålrør normaltykke | Nivå C | 515.768 | +TS=332.002 | SPRINKEL | 0 | 25 | ORIGINAL | 33.8 | 33.8 | 516.4
3 x Stålrør normaltykke | Nivå C | 2365.24 | +TS=332.002 | SPRINKEL | 0 | 25 | ORIGINAL | 33.8 | 33.8 | 2365.2
2 x Stålrør normaltykke | Nivå C | 2917.8 | +TS=332.002 | SPRINKEL | 0 | 65 | ORIGINAL | 76 | 76 | 2917.8
Stålrør normaltykke | Nivå C | 2932.4 | +TS=332.002 | SPRINKEL | 0 | 65 | ORIGINAL | 76 | 76 | 2932.4
Stålrør normaltykke | Nivå C | 1286.52 | +TS=332.002 | SPRINKEL | 0 | 65 | ORIGINAL | 76 | 76 | 1286.5
Stålrør normaltykke | Nivå C | 892.456 | +TS=332.002 | SPRINKEL | 0 | 65 | ORIGINAL | 76 | 76 | 892.5
Stålrør normaltykke | Nivå D | 1791.31 | +TS=332.008 | SPRINKEL | 0 | 25 | ORIGINAL | 33.8 | 33.8 | 1790.7
Stålrør normaltykke | Nivå D | 68.999 | +TS=332.008 | SPRINKEL | 0 | 25 | ORIGINAL | 33.8 | 33.8 | 68.6
Stålrør normaltykke | Nivå D | 330.752 | 33= Våt Kopi 1 | 33 Brannslokking våt | 0 | 25 | ORIGINAL | 33.8 | 33.8 | 331.2
Stålrør normaltykke | Nivå D | 333.8 | 33= Våt Kopi 1 | 33 Brannslokking våt | 0 | 25 | ORIGINAL | 33.8 | 33.8 | 334
Stålrør normaltykke | Nivå D | 219.833 | +TS=332.008 | SPRINKEL | 0 | 25 | ORIGINAL | 33.8 | 33.8 | 220.4
Stålrør normaltykke | Nivå D | 340.752 | +TS=332.008 | SPRINKEL | 0 | 25 | ORIGINAL | 33.8 | 33.8 | 340.8
Stålrør normaltykke | Nivå D | 333.8 | +TS=332.008 | SPRINKEL | 0 | 25 | ORIGINAL | 33.8 | 33.8 | 334
Stålrør normaltykke | Nivå D | 66.499 | +TS=332.008 | SPRINKEL | 0 | 25 | ORIGINAL | 33.8 | 33.8 | 66.1
Stålrør normaltykke | Nivå D | 13.8 | +TS=332.008 | SPRINKEL | 0 | 25 | ORIGINAL | 33.8 | 14.4 | 33.8
Stålrør normaltykke | Nivå D | 113.629 | +TS=332.008 | SPRINKEL | 0 | 25 | ORIGINAL | 33.8 | 33.8 | 114.3
Stålrør normaltykke | Nivå D | 457.802 | +TS=332.008 | SPRINKEL | 0 | 25 | ORIGINAL | 33.8 | 33.8 | 458.3
Stålrør normaltykke | Nivå D | 2657.96 | +TS=332.008 | SPRINKEL | 0 | 25 | ORIGINAL | 33.8 | 33.8 | 2658
Stålrør normaltykke | Nivå D | 349.112 | +TS=332.008 | SPRINKEL | 0 | 40 | ORIGINAL | 48.2 | 48.2 | 348.6
Stålrør normaltykke | Nivå D | 339.2 | +TS=332.008 | SPRINKEL | 0 | 25 | ORIGINAL | 33.8 | 33.8 | 338.8
Stålrør normaltykke | Nivå D | 1706.2 | +TS=332.008 | SPRINKEL | 0 | 25 | ORIGINAL | 33.8 | 33.8 | 1706.2
Stålrør normaltykke | Nivå D | 122.4 | +TS=332.008 | SPRINKEL | 0 | 25 | ORIGINAL | 33.8 | 33.8 | 122.4
Stålrør normaltykke | Nivå D | 443.734 | +TS=332.008 | SPRINKEL | 0 | 40 | ORIGINAL | 48.2 | 48.2 | 443.7
Stålrør normaltykke | Nivå D | 1738.79 | +TS=332.008 | SPRINKEL | 0 | 25 | ORIGINAL | 33.8 | 33.8 | 1738.6
Stålrør normaltykke | Nivå D | 335.975 | +TS=332.008 | SPRINKEL | 0 | 25 | ORIGINAL | 33.8 | 33.8 | 335.8
Stålrør normaltykke | Nivå D | 99.75 | +TS=332.008 | SPRINKEL | 0 | 25 | ORIGINAL | 33.8 | 33.8 | 100.2
2 x Stålrør normaltykke | Nivå D | 112.4 | +TS=332.008 | SPRINKEL | 0 | 25 | ORIGINAL | 33.8 | 33.8 | 111.9
Stålrør normaltykke | Nivå D | 532.4 | +TS=332.008 | SPRINKEL | 0 | 25 | ORIGINAL | 33.8 | 33.8 | 532.4
Stålrør normaltykke | Nivå D | 608.362 | +TS=332.008 | SPRINKEL | 0 | 25 | ORIGINAL | 33.8 | 33.8 | 608.3
Stålrør normaltykke | Nivå D | 562.158 | +TS=332.008 | SPRINKEL | 0 | 25 | ORIGINAL | 33.8 | 33.8 | 561.7
Stålrør normaltykke | Nivå D | 1148.25 | +TS=332.008 | SPRINKEL | 0 | 25 | ORIGINAL | 33.8 | 33.8 | 1147.7
Stålrør normaltykke | Nivå D | 2996.32 | +TS=332.008 | SPRINKEL | 0 | 25 | ORIGINAL | 33.8 | 33.8 | 2996.3
Stålrør normaltykke | Nivå D | 1982.16 | +TS=332.008 | SPRINKEL | 0 | 25 | ORIGINAL | 33.8 | 33.8 | 1982.2
2 x Stålrør normaltykke | Nivå D | 65.966 | +TS=332.008 | SPRINKEL | 0 | 25 | ORIGINAL | 33.8 | 33.8 | 66.1
Stålrør normaltykke | Nivå D | 115.175 | +TS=332.008 | SPRINKEL | 0 | 40 | ORIGINAL | 48.2 | 48.2 | 115.2
Stålrør normaltykke | Nivå D | 103.2 | +TS=332.008 | SPRINKEL | 0 | 40 | ORIGINAL | 48.2 | 48.2 | 103.2
Stålrør normaltykke | Nivå D | 1640.1 | +TS=332.008 | SPRINKEL | 0 | 32 | ORIGINAL | 42.4 | 42.4 | 1640.1
Stålrør normaltykke | Nivå D | 18.788 | +TS=332.008 | SPRINKEL | 0 | 40 | ORIGINAL | 48.2 | 48.2 | 19.2
Stålrør normaltykke | Nivå D | 293.31 | +TS=332.008 | SPRINKEL | 0 | 25 | ORIGINAL | 33.8 | 33.8 | 293
Stålrør normaltykke | Nivå D | 379.858 | +TS=332.008 | SPRINKEL | 0 | 25 | ORIGINAL | 33.8 | 33.8 | 379.8
Stålrør normaltykke | Nivå D | 273.641 | +TS=332.008 | SPRINKEL | 0 | 25 | ORIGINAL | 33.8 | 33.8 | 273.5
Stålrør normaltykke | Nivå D + 1,2 m | 90.298 | 33= Våt Kopi 29 | 33 Brannslokking våt | 0 | 25 | ORIGINAL | 33.8 | 33.8 | 90.1
Stålrør normaltykke | Nivå D + 1,2 m | 90.298 | 33= Våt Kopi 40 | 33 Brannslokking våt | 0 | 25 | ORIGINAL | 33.8 | 33.8 | 90.1
Stålrør normaltykke | Nivå D + 1,2 m | 90.298 | 33= Våt Kopi 43 | 33 Brannslokking våt | 0 | 25 | ORIGINAL | 33.8 | 33.8 | 90.1
Stålrør normaltykke | Nivå D + 1,2 m | 407.25 | 33= Våt Kopi 48 | 33 Brannslokking våt | 0 | 25 | ORIGINAL | 33.8 | 33.8 | 406.9
Stålrør normaltykke | Nivå D + 1,2 m | 80.298 | 33= Våt Kopi 47 | 33 Brannslokking våt | 0 | 25 | ORIGINAL | 33.8 | 33.8 | 79.6
Stålrør normaltykke | Nivå C |  | +TS=332.002 | SPRINKEL |  |  | RESULT | 76 | 76 | 1541

# IfcFlowTerminal: 68DGR-STD-STÅENDE (14)
In: Nivå C
Type - Description: Spray, Upright installation, STD, K=80
ePset_Simplebim - Assembly Level: Leaf
ePset_LocationTool - Splitting: ORIGINAL
MagiCAD Pset_Sprinkler - Manufacturer: General; KFactor: 80; Nominal Release Temperature [°C]: 68; Description: Spray, Upright installation, STD, K=80
Group: +TS=332.002

# IfcFlowTerminal: BLP-K115-141C-STD (2)
In: Nivå D
Type - Description: Standard Response bulb thermal element, K=115
ePset_Simplebim - Assembly Level: Leaf
MagiCAD Pset_Sprinkler - KFactor: 115; Nominal Release Temperature [°C]: 141; Product code: BLP-K115-141C-STD; Description: Standard Response bulb thermal element, K=115; Manufacturer: Generic China
ePset_LocationTool - Splitting: ORIGINAL
Name | Group
BLP-K115-141C-STD | 33= Våt Kopi 1
BLP-K115-141C-STD | 33= Våt Kopi 27

# IfcFlowTerminal: Data socket-2 (11)
In: Nivå D
Type - Description: Data uttak dobbel Vegg_TVO; PredefinedType: COMMUNICATIONSOUTLET
Pset_OutletTypeCommon - IsPluggableOutlet: yes
ePset_Simplebim - Assembly Level: Leaf
ePset_LocationTool - Splitting: ORIGINAL
MagiCAD Pset_Device - IP_Code: IP20; System code: 574; Length [mm]: 0 mm; P2: 2; Manufacturer: General; Width [mm]: 22 mm; Height [mm]: 71 mm; P1: TVO; Product code: Data socket-2
AVINOR - 08_Status: S4; 07_Fase: F90; 02_Prosjekt: 10004394; 04_Kontrakt: 188962; 03_Ansvar: 187259; 01_Lufthavnkode: ENGM
Pset_ElectricalDeviceCommon - IP_Code: IP20
Group: Spredenett
Name | 05_ID-nummer
Data socket-2 | +TS=574.007-WD1037
Data socket-2 | +TS=574.007-WD0720
Data socket-2 | +TS=574.007-WD0817CP
Data socket-2 | +TS=574.007-WD0825CP
Data socket-2 | +TS=574.007-WD1081
Data socket-2 | +TS=574.007-WD1079
Data socket-2 | +TS=574.007-WD0044
Data socket-2 | +TS=574.007-WD0042
Data socket-2 | +TS=574.007-WD1077
Data socket-2 | +TS=574.007-WD0817
Data socket-2 | +TS=574.007-WD0825

# IfcFlowTerminal: Datauttak enkelt Vegg - IKT (5)
In: Nivå D
Type - Description: Datauttak enkelt Vegg - IKT; PredefinedType: COMMUNICATIONSOUTLET
Pset_OutletTypeCommon - IsPluggableOutlet: yes
ePset_Simplebim - Assembly Level: Leaf
AVINOR - 08_Status: S4; 07_Fase: F90; 02_Prosjekt: 10004394; 04_Kontrakt: 188962; 03_Ansvar: 187259; 01_Lufthavnkode: ENGM
MagiCAD Pset_Device - System code: 574; User code: -WD; Length [mm]: 0 mm; Width [mm]: 0 mm; Height [mm]: 0 mm
ePset_LocationTool - Splitting: ORIGINAL
Group: Spredenett
Name | 05_ID-nummer
Datauttak enkelt Vegg - IKT | +TS=574.007-WD1038CP
Datauttak enkelt Vegg - IKT | +TS=574.007-WD0720CP
Datauttak enkelt Vegg - IKT | +TS=574.007-WD0729CP
Datauttak enkelt Vegg - IKT | +TS=574.007-WD1038
Datauttak enkelt Vegg - IKT | +TS=574.007-WD1036

# IfcFlowTerminal: IB7105 Ledelys innfelt i himling:IB7105 Zumtobel Resclite C Antipanic ED NDA WH (2)
In: Nivå D
Type - Material: <Unnamed>
Type - Pset_ManufacturerTypeInformation - Manufacturer: Zumtobel
ePset_Simplebim - Assembly Level: Leaf
Pset_DistributionFlowElementCommon - Reference: IB7105 Zumtobel Resclite C Antipanic ED NDA WH; sets with these values: 2
ePset_LocationTool - Splitting: ORIGINAL
AVINOR - 08_Status: S4; 07_Fase: F90; 04_Kontrakt: 188999; 02_Prosjekt: 10004394; 05_ID-nummer: +OO=443.000-IB7105; 03_Ansvar: 187259; 06_Omrade: TS; 01_Lufthavnkode: ENGM
Name (IB7105 Ledelys innfelt i himling:IB7105 Zumtobel Resclite C Antipanic ED NDA WH:...)
24788155 | Group: 2
24788283

# IfcFlowTerminal: IB7330 Markeringslys ensidig 30 meter leseavstand innfelt:IB7330 Zumtobel Puresign/Comsign 150 ED NDA (2)
In: Nivå D
Type - Material: <Unnamed>, Light Source Hvit, Light Source Grønn
Type - Pset_ManufacturerTypeInformation - Manufacturer: Zumtobel
ePset_Simplebim - Assembly Level: Leaf
Pset_QuantityTakeOff - Reference: IB7330 Zumtobel Puresign/Comsign 150 ED NDA; sets with these values: 2
ePset_LocationTool - Splitting: ORIGINAL
AVINOR - 08_Status: S4; 07_Fase: F90; 05_ID-nummer: +TO=443.001-IB7330; 06_Omrade: TS; 01_Lufthavnkode: ENGM; 02_Prosjekt: A173787; 04_Kontrakt: A173787
Group: 1
Name (IB7330 Markeringslys ensidig 30 meter leseavstand innfelt:IB7330 Zumtobel Puresign/Comsign 150 ED NDA:...)
19542616
19542617

# IfcFlowTerminal: IB7333 Markeringslys ensidig 30 meter leseavstand vegg:IB7333 Zumtobel Puresign 150 AW NDA, IB7333 Markeringslys ensidig 30 meter leseavstand vegg:IB7333 Zumtobel Puresign 150 AW NDA:24787859
In: Nivå D
Type - Material: Light Source Hvit, Light Source Grønn, <Unnamed>
Type - Pset_ManufacturerTypeInformation - Manufacturer: Zumtobel
ePset_Simplebim - Assembly Level: Leaf
Pset_DistributionFlowElementCommon - Reference: IB7333 Zumtobel Puresign 150 AW NDA; sets with these values: 2
AVINOR - 08_Status: S4; 07_Fase: F90; 04_Kontrakt: 188999; 05_ID-nummer: +TO=443.001-IB7333; 02_Prosjekt: 10004394; 03_Ansvar: 187259; 06_Omrade: TS; 01_Lufthavnkode: ENGM
ePset_LocationTool - Splitting: ORIGINAL
Group: 1

# IfcFlowTerminal: IB7404 Ledelys utenpåliggende:IB7404 Zumtobel Resclite C Antipanic AD NDA WH (5)
In: Nivå C
Type - Material: <Unnamed>
Type - Pset_ManufacturerTypeInformation - Manufacturer: ZUMTOBEL
ePset_Simplebim - Assembly Level: Leaf
ePset_LocationTool - Splitting: ORIGINAL
Pset_DistributionFlowElementCommon - Reference: IB7404 Zumtobel Resclite C Antipanic AD NDA WH; sets with these values: 2
AVINOR - 08_Status: S4; 02_Prosjekt: A172140; 07_Fase: F50; 03_Ansvar: 181608; 04_Kontrakt: 184990; 05_ID-nummer: +TO=443.001-IB7404; 06_Omrade: TS; 01_Lufthavnkode: ENGM
Name (IB7404 Ledelys utenpåliggende:IB7404 Zumtobel Resclite C Antipanic AD NDA WH:...) | Group
18524484 | 3
18524488 | 3
18524501
18528150
18528168 | 4

# IfcFlowTerminal: Orion-LOV-TA-315+Luna-315-315 (2)
In: Nivå D
Type - Description: ATD for panneld ceiling
Classification: VE1.13332 Not defined (NS3420); Group: +TS=360.034 T (1)
ePset_Simplebim - Assembly Level: Leaf
ePset_LocationTool - Splitting: ORIGINAL

# IfcFlowTerminal: Pølsehette 1500x1000 arrivals east ø315
In: Nivå D
ePset_Simplebim - Assembly Level: Leaf
ePset_LocationTool - Splitting: ORIGINAL
Group: +TS=360.050 A

# IfcFlowTerminal: SP-15-K80-68DGR-STD (5)
In: Nivå D
Type - Description: Spray, pendent installation, STD, K=80
ePset_Simplebim - Assembly Level: Leaf
ePset_LocationTool - Splitting: ORIGINAL
MagiCAD Pset_Sprinkler - User Code: HIMLING; Product code: SP-15-K80-68DGR-STD; Description: Spray, pendent installation, STD, K=80; Manufacturer: General; KFactor: 80; Nominal Release Temperature [°C]: 68
Name | Group
2 x SP-15-K80-68DGR-STD | 33= Våt Kopi 1
3 x SP-15-K80-68DGR-STD | +TS=332.008

# IfcFlowTerminal: SP-15-K80-68DGR-STD-STÅENDE (5)
In: Nivå D + 1,2 m
Type - Description: Spray, pendent installation, STD, K=80
Classification: RS1.3000121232 Not defined (NS3420)
ePset_Simplebim - Assembly Level: Leaf
MagiCAD Pset_Sprinkler - User Code: UZ03T; NationalCode: RS1.3000121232; Product code: SP-15-K80-68DGR-STD; Description: Spray, pendent installation, STD, K=80; Manufacturer: General; KFactor: 80; Nominal Release Temperature [°C]: 68
ePset_LocationTool - Splitting: ORIGINAL
Name | Group
SP-15-K80-68DGR-STD-STÅENDE | 33= Våt Kopi 29
SP-15-K80-68DGR-STD-STÅENDE | 33= Våt Kopi 40
SP-15-K80-68DGR-STD-STÅENDE | 33= Våt Kopi 43
SP-15-K80-68DGR-STD-STÅENDE | 33= Våt Kopi 48
SP-15-K80-68DGR-STD-STÅENDE | 33= Våt Kopi 47

# IfcRailing: Railing:A247 Fendring - FE-S01 - Avviser, montert m. brakett mot dekke, 1 rør Ø=49 mm (2)
In: Nivå D
Material: <Unnamed>
ePset_Simplebim - Assembly Level: Leaf
ePset_LocationTool - Splitting: ORIGINAL
ePset_SimplebimBasicQuantities - Height: 43.3013 mm
Pset_RailingCommon - Height: 1219.2 mm; Reference: A247 Fendring - FE-S01 - Avviser, montert m. brakett mot dekke, 1 rør Ø=49 mm; IsExternal: no
AVINOR - 07_Fase: F90; 03_Ansvar: FDV; 08_Status: S2; 06_Omrade: TS; 01_Lufthavnkode: ENGM
Pset_QuantityTakeOff - Reference: A247 Fendring - FE-S01 - Avviser, montert m. brakett mot dekke, 1 rør Ø=49 mm
Name (Railing:A247 Fendring - FE-S01 - Avviser, montert m. brakett mot dekke, 1 rør Ø=49 mm:...) | Width (mm) | Length (mm)
30672881 | 950 | 2550
32536178 | 920.074 | 6723.5

# IfcSlab: 130*45000 (2)
In: D
Description: 130*45000; PredefinedType: FLOOR
ePset_SimplebimBasicQuantities - Perimeter (Simplebim): 51825 mm; Area, top, net (Simplebim): 138.841 m2; Area, largest surface, net (Simplebim): 138.841 m2; Volume, net (Simplebim): 18.0493 m3; Area, sides, net (Simplebim): 6.73725 m2; Thickness (Simplebim): 130 mm
ePset_Simplebim - Assembly Level: Leaf
Pset_SlabCommon - Reference: Concrete-10274(?); LoadBearing: no
ePset_LocationTool - Splitting: RESULT
AVINOR - 08_Status: S2; 06_Omrade: TS; 01_Lufthavnkode: ENGM
Tekla Common - Part mark: Concrete-10274(?); Name: PÅSTØP; Bottom elevation: +203.800; Assembly mark: PST-757(?); Grade: C30/37; Top elevation: +203.930; Profile: 130*45000; Class: 262
Name | 07_Fase | 02_Prosjekt | 03_Ansvar
PÅSTØP | F20 | A181143 | 187259
PÅSTØP | F90 | T1 | FDV | AVINOR - 04_Kontrakt: FDV

# IfcSlab: Floor:A254 - Gulvoppbygging m_f.o - 70 mm, Floor:A254 - Gulvoppbygging m_f.o - 70 mm:34265622
In: Nivå D
Type - PredefinedType: FLOOR; Material: _NSW Gulv (Generell) 70 mm
AVINOR - 07_Fase: F90; 08_Status: S1; 03_Ansvar: FDV; 06_Omrade: TS; 01_Lufthavnkode: ENGM
ePset_Simplebim - Assembly Level: Leaf
ePset_SimplebimBasicQuantities - Perimeter (Simplebim): 51674.8 mm; Area, sides, net (Simplebim): 3.61724 m2; Thickness (Simplebim): 70 mm; Volume, net (Simplebim): 9.7677 m3; Area, top, net (Simplebim): 139.539 m2; Area, largest surface, net (Simplebim): 139.539 m2
ePset_LocationTool - Splitting: RESULT
Pset_ReinforcementBarPitchOfSlab - Reference: A254 - Gulvoppbygging m_f.o - 70 mm; sets with these values: 2
Pset_SlabCommon - IsExternal: no; LoadBearing: no; Reference: A254 - Gulvoppbygging m_f.o - 70 mm

# IfcSlab: HD400 (17)
In: D
Description: HD400; PredefinedType: FLOOR
ePset_Simplebim - Assembly Level: Leaf
AVINOR - 07_Fase: F90; 02_Prosjekt: T1; 04_Kontrakt: FDV; 03_Ansvar: FDV; 08_Status: S2; 06_Omrade: TS; 01_Lufthavnkode: ENGM
Tekla Common - Top elevation: +203.800; Profile: HD400; Grade: C45/55; Name: HULLDEKKE; Bottom elevation: +203.400; Class: 162
ePset_SimplebimBasicQuantities - Thickness (Simplebim): 400 mm
Pset_SlabCommon - LoadBearing: no
ePset_LocationTool - Splitting: RESULT
Name | Assembly mark | Part mark = Reference | Area, sides, net (Simplebim) (m2) | Perimeter (Simplebim) (mm) | Area, top, net (Simplebim) (m2) | Area, largest surface, net (Simplebim) (m2) | Volume, net (Simplebim) (m3)
2 x HULLDEKKE | HD-1621 | Concrete-8989 | 12.0504 | 30126.1 | 5.83471 | 4.01291 | 0.679071
6 x HULLDEKKE | HD-1619 | Concrete-8987 | 25.6512 | 64128 | 12.4217 | 8.77811 | 1.58814
HULLDEKKE | HD-1623 | Concrete-8991 | 18.0088 | 45022 | 8.81273 | 6.25143 | 1.12048
2 x HULLDEKKE | HD-1620 | Concrete-8988 | 15.9707 | 39926.7 | 8.29868 | 5.74331 | 1.00126
5 x HULLDEKKE | HD-981 | Concrete-323 | 25.6512 | 64128 | 12.4217 | 8.77811 | 1.58814
HULLDEKKE | HD-1622 | Concrete-8990 | 18.0088 | 45022 | 8.81274 | 6.25143 | 1.12048

# IfcSystem (21)
Name | Description
+TS=360.034 T (1) | +TS=360.034 T (1)
+TS=360.034 A (1) | +TS=360.034 A (1)
+TS=360.050 A | +TS=360.050 A
+TS=332.002 | +TS=332.002
+TS=332.008 | +TS=332.008
33= Våt Kopi 1 | 33= Våt Kopi 1
33= Våt Kopi 27 | 33= Våt Kopi 27
33= Våt Kopi 29 | 33= Våt Kopi 29
33= Våt Kopi 40 | 33= Våt Kopi 40
33= Våt Kopi 43 | 33= Våt Kopi 43
33= Våt Kopi 48 | 33= Våt Kopi 48
33= Våt Kopi 47 | 33= Våt Kopi 47
- | 574 | AVINOR - 08_Status: S4; 07_Fase: F90; 04_Kontrakt: 72512; 02_Prosjekt: 72101; 01_Lufthavnkode: ENGM; 05_ID-nummer: +TS=574.006-WD0276; MagiCAD Pset_System - Code: 574
Spredenett | 574 | AVINOR - 08_Status: S4; 07_Fase: F90; 04_Kontrakt: A173806; 02_Prosjekt: A173806; 01_Lufthavnkode: ENGM; 05_ID-nummer: +TQ=574.001-WD1140; MagiCAD Pset_System - Code: 574; Description: Spredenett
Brannalarm | 542 | AVINOR - 08_Status: S2; 07_Fase: F90; 04_Kontrakt: FDV; 02_Prosjekt: 72101; 01_Lufthavnkode: ENGM; 05_ID-nummer: +TO=542.024; MagiCAD Pset_System - Code: 542; Description: Brannalarm
3
4
2
1
Adgangskontroll, Innbruddsalarm | 543 | AVINOR - 08_Status: S4; 07_Fase: F90; 04_Kontrakt: 72561; 02_Prosjekt: 72101; 01_Lufthavnkode: ENGM; 05_ID-nummer: +TS=543.003-QG6301; 03_Ansvar: T20100; MagiCAD Pset_System - Code: 543; Description: Adgangskontroll, Innbruddsalarm
Bæresystem for elkraft | 4111 | MagiCAD Pset_System - Code: 4111; Description: Bæresystem for elkraft

# IfcWall: 7480*300 (2)
In: B
Description: 7480*300
ePset_Simplebim - Assembly Level: Leaf
ePset_LocationTool - Splitting: RESULT
Tekla Common - Name: PLASSTØPTVEGG; Top elevation: +203.780; Profile: 7480*300; Class: 250; Part mark: Concrete-9181; Grade: C35/45; Bottom elevation: +196.300
ePset_SimplebimBasicQuantities - Area, side, gross, AABB (Simplebim): 3.6075 m2; Volume, net (Simplebim): 1.08225 m3; Thickness (Simplebim): 300 mm; Height (Simplebim): 780 mm; Length (Simplebim): 4625 mm; Area, largest surface, net (Simplebim): 3.6075 m2; Area, side, net, average (Simplebim): 3.6075 m2; Area, side, gross, larger (Simplebim): 3.6075 m2; Area, side, gross, average (Simplebim): 3.6075 m2; Area, side, net, smaller (Simplebim): 3.6075 m2; Area, side, net, larger (Simplebim): 3.6075 m2; Area, side, gross, smaller (Simplebim): 3.6075 m2
Pset_WallCommon - LoadBearing: no; Reference: Concrete-9181
AVINOR - 07_Fase: F90; 02_Prosjekt: T1; 03_Ansvar: FDV; 04_Kontrakt: FDV; 08_Status: S2; 06_Omrade: TS; 01_Lufthavnkode: ENGM
Name | Assembly mark
PLASSTØPTVEGG | PLV-1544
PLASSTØPTVEGG | PLV-2838

# IfcWall: Basic Wall:A241 - MH-142 (Multiblokk 142) (2)
In: Nivå C + 2,03 m
Type - PredefinedType: STANDARD; Material: Betong - Multiblokk 142 mm
Type - Pset_ReinforcementBarPitchOfWall - Description: Hulmur murblokk
ePset_Simplebim - Assembly Level: Leaf
AVINOR - 07_Fase: F90; 03_Ansvar: FDV; 08_Status: S2; 06_Omrade: TS; 01_Lufthavnkode: ENGM
Pset_WallCommon - IsExternal: no; ExtendToStructure: no; LoadBearing: no; Reference: A241 - MH-142 (Multiblokk 142)
Pset_QuantityTakeOff - Reference: A241 - MH-142 (Multiblokk 142); sets with these values: 2
ePset_SimplebimBasicQuantities - Thickness (Simplebim): 142 mm; Height (Simplebim): 400 mm
ePset_LocationTool - Splitting: RESULT
Name (Basic Wall:A241 - MH-142 (Multiblokk 142):...) | Area, side, gross, AABB (Simplebim) (m2) | Area, side, net, average (Simplebim) (m2) = Area, largest surface, net (Simplebim) (m2) = Area, side, gross, larger (Simplebim) (m2) = Area, side, net, smaller (Simplebim) (m2) = Area, side, gross, average (Simplebim) (m2) = Area, side, gross, smaller (Simplebim) (m2) = Area, side, net, larger (Simplebim) (m2) | Volume, net (Simplebim) (m3) | Length (Simplebim) (mm)
2418993 | 2.9652 | 2.9654 | 0.421087 | 7413 | Identity Data - CQFireRequirement: EI 60/ A2-s1,d0
2418987 | 1.2252 | 1.22522 | 0.173982 | 3063

# IfcWall: Basic Wall:A241 - MH-187 (Multiblokk 187), Basic Wall:A241 - MH-187 (Multiblokk 187):2365684
In: Nivå C + 2,03 m
Type - PredefinedType: STANDARD; Material: Betong - Multiblokk 187 mm
Type - Pset_ReinforcementBarPitchOfWall - Description: Hulmur murblokk
Identity Data - CQFireRequirement: EI 60/ A2-s1,d0
ePset_Simplebim - Assembly Level: Leaf
AVINOR - 07_Fase: F90; 03_Ansvar: FDV; 08_Status: S2; 06_Omrade: TS; 01_Lufthavnkode: ENGM
ePset_LocationTool - Splitting: RESULT
Pset_QuantityTakeOff - Reference: A241 - MH-187 (Multiblokk 187); sets with these values: 2
Pset_WallCommon - IsExternal: no; ExtendToStructure: no; LoadBearing: no; Reference: A241 - MH-187 (Multiblokk 187)
ePset_SimplebimBasicQuantities - Area, side, gross, AABB (Simplebim): 2.9652 m2; Area, side, net, average (Simplebim): 2.9654 m2; Area, largest surface, net (Simplebim): 2.9654 m2; Area, side, gross, larger (Simplebim): 2.9654 m2; Area, side, net, smaller (Simplebim): 2.9654 m2; Area, side, gross, average (Simplebim): 2.9654 m2; Area, side, gross, smaller (Simplebim): 2.9654 m2; Area, side, net, larger (Simplebim): 2.9654 m2; Thickness (Simplebim): 187 mm; Height (Simplebim): 400 mm; Length (Simplebim): 7413 mm; Volume, net (Simplebim): 0.55453 m3

# IfcWall: Basic Wall:A241 - MK-142 (Multiblokk 142), Basic Wall:A241 - MK-142 (Multiblokk 142):2418989
In: Nivå C + 2,03 m
Type - PredefinedType: STANDARD; Material: Betong - Multiblokk 142 mm
Type - Pset_ReinforcementBarPitchOfWall - Description: Uisolert murblokk
ePset_Simplebim - Assembly Level: Leaf
AVINOR - 07_Fase: F90; 03_Ansvar: FDV; 08_Status: S2; 06_Omrade: TS; 01_Lufthavnkode: ENGM
ePset_LocationTool - Splitting: RESULT
Pset_WallCommon - Reference: A241 - MK-142 (Multiblokk 142); IsExternal: no; ExtendToStructure: no; LoadBearing: no
Identity Data - CQFireRequirement: REI 120-M/ A2-s1,d0
Pset_QuantityTakeOff - Reference: A241 - MK-142 (Multiblokk 142); sets with these values: 2
ePset_SimplebimBasicQuantities - Area, side, gross, AABB (Simplebim): 0.8628 m2; Area, side, net, larger (Simplebim): 0.805819 m2; Area, side, gross, smaller (Simplebim): 0.805819 m2; Area, side, gross, average (Simplebim): 0.805819 m2; Area, side, net, smaller (Simplebim): 0.805819 m2; Area, side, gross, larger (Simplebim): 0.805819 m2; Area, largest surface, net (Simplebim): 0.805819 m2; Area, side, net, average (Simplebim): 0.805819 m2; Thickness (Simplebim): 142 mm; Height (Simplebim): 400 mm; Length (Simplebim): 2157 mm; Volume, net (Simplebim): 0.114426 m3

# IfcWallStandardCase: Basic Wall:A241 - MK-142 (Multiblokk 142) (4)
Type - PredefinedType: STANDARD; Material: Betong - Multiblokk 142 mm
Type - Pset_ReinforcementBarPitchOfWall - Description: Uisolert murblokk
ePset_Simplebim - Assembly Level: Leaf
AVINOR - 07_Fase: F90; 03_Ansvar: FDV; 08_Status: S2; 06_Omrade: TS; 01_Lufthavnkode: ENGM
ePset_SimplebimBasicQuantities - Length (Simplebim): 4050 mm; Thickness (Simplebim): 142 mm
Pset_WallCommon - Reference: A241 - MK-142 (Multiblokk 142); IsExternal: no; ExtendToStructure: no; LoadBearing: no
ePset_LocationTool - Splitting: ORIGINAL
Pset_QuantityTakeOff - Reference: A241 - MK-142 (Multiblokk 142); sets with these values: 2
Identity Data - CQFireRequirement: EI 60/A2-s1,d0
Name (Basic Wall:A241 - MK-142 (Multiblokk 142):...) | In | Height (Simplebim) (mm) | Volume, net (Simplebim) (m3) | Area, side, gross, larger (Simplebim) (m2) = Area, largest surface, net (Simplebim) (m2) = Area, side, net, average (Simplebim) (m2) = Area, side, net, larger (Simplebim) (m2) = Area, side, gross, smaller (Simplebim) (m2) = Area, side, gross, average (Simplebim) (m2) = Area, side, net, smaller (Simplebim) (m2) = Area, side, gross, AABB (Simplebim) (m2)
2420329 | Nivå D | 1400 | 0.80514 | 5.67
2420329 | Nivå D + 1,2 m | 2170 | 1.24797 | 8.7885
2420330 | Nivå D | 1400 | 0.80514 | 5.67
2420330 | Nivå D + 1,2 m | 2170 | 1.24797 | 8.7885

# IfcWallStandardCase: Basic Wall:A241 - SVS-102 (100/100 gx-xg) (8)
Type - PredefinedType: STANDARD; Material: Plate - Gips 12.5 mm, _NSW X-finer 12 mm, _NSW Stålstender, uisolert 100 mm, _NSW X-finer 12 mm, Plate - Gips 12.5 mm
Type - Pset_ReinforcementBarPitchOfWall - Description: Stendervegg: 2x12.5mm Gipsplater - 100mm Stålstender - 2x12.5mm Gipsplater
ePset_Simplebim - Assembly Level: Leaf
ePset_SimplebimBasicQuantities - Thickness (Simplebim): 149 mm
Pset_QuantityTakeOff - Reference: A241 - SVS-102 (100/100 gx-xg); sets with these values: 2
AVINOR - 07_Fase: F90; 03_Ansvar: FDV; 08_Status: S2; 06_Omrade: TS; 01_Lufthavnkode: ENGM
ePset_LocationTool - Splitting: ORIGINAL
Pset_WallCommon - IsExternal: no; ExtendToStructure: no; LoadBearing: no; Reference: A241 - SVS-102 (100/100 gx-xg)
Name (Basic Wall:A241 - SVS-102 (100/100 gx-xg):...) | In | Length (Simplebim) (mm) | Volume, net (Simplebim) (m3) | Area, side, gross, smaller (Simplebim) (m2) = Area, side, gross, average (Simplebim) (m2) = Area, side, gross, larger (Simplebim) (m2) | Area, side, net, smaller (Simplebim) (m2) = Area, side, net, larger (Simplebim) (m2) = Area, side, net, average (Simplebim) (m2) | Height (Simplebim) (mm) | Area, side, gross, AABB (Simplebim) (m2) | Area, largest surface, net (Simplebim) (m2)
30610668 | Nivå D | 7613.5 | 1.18071 | 10.0553 | 7.9242 | 1200 | 9.1362 | 7.7682
30610668 | Nivå D + 1,2 m | 7613.5 | 2.1886 | 16.8197 | 14.6886 | 2050 | 15.6077 | 14.6886
30610946 | Nivå D | 420.861 | 0.07525 | 0.505033 | 0.505033 | 1200 | 0.505033 | 0.505033
30610946 | Nivå D + 1,2 m | 420.861 | 0.128552 | 0.862765 | 0.862765 | 2050 | 0.862765 | 0.862765
30611155 | Nivå D | 563.452 | 0.100745 | 0.676143 | 0.676143 | 1200 | 0.676143 | 0.676143
30611155 | Nivå D + 1,2 m | 563.452 | 0.172106 | 1.15508 | 1.15508 | 2050 | 1.15508 | 1.15508
30611230 | Nivå D | 7539.5 | 1.34806 | 9.0474 | 9.0474 | 1200 | 9.0474 | 9.0474
30611230 | Nivå D + 1,2 m | 7539.5 | 2.30294 | 15.456 | 15.456 | 2050 | 15.456 | 15.456

# IfcWallStandardCase: Basic Wall:A241 - SVS-75 (75/75 g-g) (12)
Type - PredefinedType: STANDARD; Material: Plate - Gips 12.5 mm, _NSW Stålstender, uisolert 75 mm, Plate - Gips 12.5 mm
Type - Pset_ReinforcementBarPitchOfWall - Description: Tilsvarende: T2 - IVEGG-100 - Forprosjekt
ePset_Simplebim - Assembly Level: Leaf
AVINOR - 07_Fase: F90; 03_Ansvar: FDV; 08_Status: S2; 06_Omrade: TS; 01_Lufthavnkode: ENGM
Pset_QuantityTakeOff - Reference: A241 - SVS-75 (75/75 g-g); sets with these values: 2
ePset_SimplebimBasicQuantities - Thickness (Simplebim): 100 mm
ePset_LocationTool - Splitting: ORIGINAL
Pset_WallCommon - Reference: A241 - SVS-75 (75/75 g-g); IsExternal: no; ExtendToStructure: no; LoadBearing: no
Name (Basic Wall:A241 - SVS-75 (75/75 g-g):...) | In | Area, side, gross, smaller (Simplebim) (m2) | Area, side, net, smaller (Simplebim) (m2) | Area, side, gross, AABB (Simplebim) (m2) | Area, side, gross, average (Simplebim) (m2) | Area, side, net, average (Simplebim) (m2) | Length (Simplebim) (mm) | Area, side, net, larger (Simplebim) (m2) | Area, side, gross, larger (Simplebim) (m2) | Area, largest surface, net (Simplebim) (m2) | Height (Simplebim) (mm) | Volume, net (Simplebim) (m3)
32536186 | Nivå D | 0.547606 | 0.547606 | 0.667606 | 0.607606 | 0.607606 | 556.339 | 0.667606 | 0.667606 | 0.667606 | 1200 | 0.0607606
32536186 | Nivå D + 1,2 m | 0.821409 | 0.821409 | 1.00141 | 0.911409 | 0.911409 | 556.339 | 1.00141 | 1.00141 | 1.00141 | 1800 | 0.0911409
32536187 | Nivå D | 4.05492 | 2.13482 | 3.34682 | 4.11492 | 2.19482 | 2789.02 | 2.25482 | 4.17492 | 1.28282 | 1200 | 0.219482
32536187 | Nivå D + 1,2 m | 5.93223 | 4.01213 | 5.02023 | 6.02223 | 4.10213 | 2789.02 | 4.19213 | 6.11223 | 4.19213 | 1800 | 0.410213
32536188 | Nivå D | 0.646255 | 0.646255 | 0.646256 | 0.646255 | 0.646255 | 538.546 | 0.646255 | 0.646255 | 0.646255 | 1200 | 0.0646256
32536188 | Nivå D + 1,2 m | 0.969383 | 0.969383 | 0.969383 | 0.969383 | 0.969383 | 538.546 | 0.969383 | 0.969383 | 0.969383 | 1800 | 0.0969383
32536189 | Nivå D | 1.46522 | 1.46522 | 1.46522 | 1.46522 | 1.46522 | 1221.02 | 1.46522 | 1.46522 | 1.46522 | 1200 | 0.146522
32536189 | Nivå D + 1,2 m | 2.19783 | 2.19783 | 2.19783 | 2.19783 | 2.19783 | 1221.02 | 2.19783 | 2.19783 | 2.19783 | 1800 | 0.219783
32536190 | Nivå D | 0.404406 | 0.404406 | 0.404406 | 0.404406 | 0.404406 | 337.005 | 0.404406 | 0.404406 | 0.404406 | 1200 | 0.0404406
32536190 | Nivå D + 1,2 m | 0.606609 | 0.606609 | 0.606609 | 0.606609 | 0.606609 | 337.005 | 0.606609 | 0.606609 | 0.606609 | 1800 | 0.0606609
32536191 | Nivå D | 4.92565 | 4.92565 | 5.04565 | 4.98565 | 4.98565 | 4204.7 | 5.04565 | 5.04565 | 5.04565 | 1200 | 0.498565
32536191 | Nivå D + 1,2 m | 7.38847 | 7.38847 | 7.56847 | 7.47847 | 7.47847 | 4204.7 | 7.56847 | 7.56847 | 7.56847 | 1800 | 0.747847
